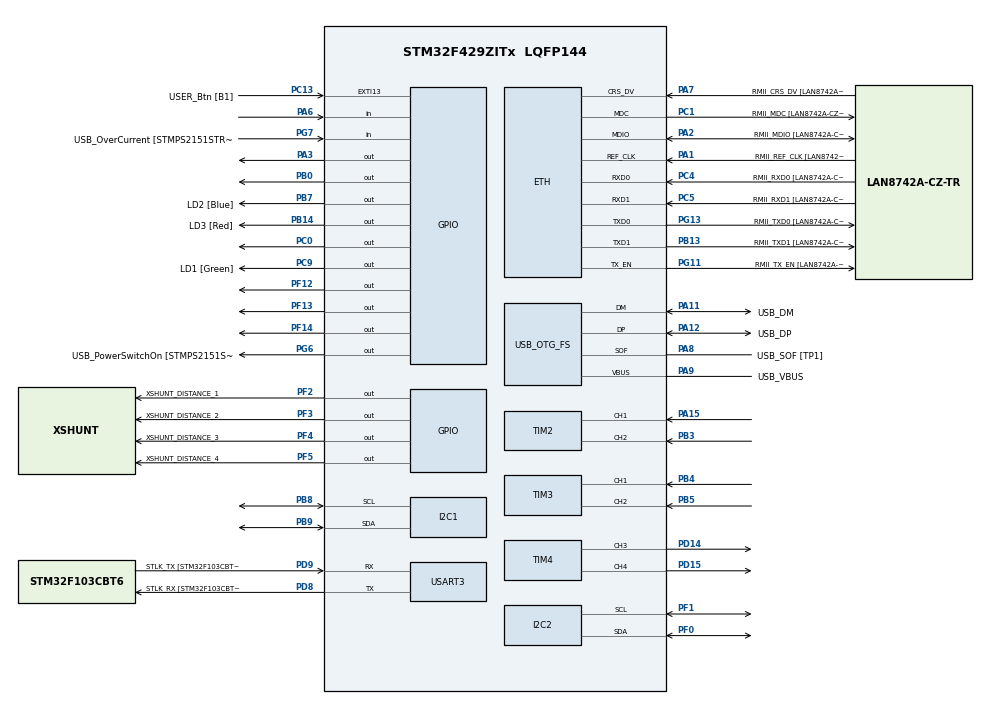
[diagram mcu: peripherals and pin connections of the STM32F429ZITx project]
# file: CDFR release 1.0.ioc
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ETH.MediaInterface=ETH_MEDIA_INTERFACE_RMII
ETH.PHY_Name=LAN8742A_PHY_ADDRESS
ETH.PHY_Value=0
ETH.PhyAddress=0
LWIP.CHECKSUM_BY_HARDWARE=1
LWIP.Version=v2.0.3_Cube
Mcu.Family=STM32F4
Mcu.Name=STM32F429ZITx
Mcu.Package=LQFP144
NVIC.OTG_FS_IRQn=true\:0\:0\:false\:false\:true\:false\:true
NVIC.PriorityGroup=NVIC_PRIORITYGROUP_4
NVIC.TIM8_UP_TIM13_IRQn=true\:5\:0\:true\:false\:true\:true\:true
PA1.GPIO_Label=RMII_REF_CLK [LAN8742A-CZ-TR_REFCLK0]
PA1.Mode=RMII
PA1.Signal=ETH_REF_CLK
PA10.GPIO_Label=USB_ID
PA10.Signal=USB_OTG_FS_ID
PA11.GPIO_Label=USB_DM
PA11.Mode=Device_Only
PA11.Signal=USB_OTG_FS_DM
PA12.GPIO_Label=USB_DP
PA12.Mode=Device_Only
PA12.Signal=USB_OTG_FS_DP
PA13.GPIO_Label=TMS
PA13.Mode=Serial_Wire
PA13.Signal=SYS_JTMS-SWDIO
PA14.GPIO_Label=TCK
PA14.Mode=Serial_Wire
PA14.Signal=SYS_JTCK-SWCLK
PA15.Signal=S_TIM2_CH1_ETR
PA2.GPIO_Label=RMII_MDIO [LAN8742A-CZ-TR_MDIO]
PA2.Mode=RMII
PA2.Signal=ETH_MDIO
PA3.Signal=GPIO_Output
PA6.Signal=GPIO_Input
PA7.GPIO_Label=RMII_CRS_DV [LAN8742A-CZ-TR_CRS_DV]
PA7.Mode=RMII
PA7.Signal=ETH_CRS_DV
PA8.GPIO_Label=USB_SOF [TP1]
PA8.Mode=Activate_SOF_FS
PA8.Signal=USB_OTG_FS_SOF
PA9.GPIO_Label=USB_VBUS
PA9.Mode=Activate_VBUS
PA9.Signal=USB_OTG_FS_VBUS
PB0.Signal=GPIO_Output
PB13.GPIO_Label=RMII_TXD1 [LAN8742A-CZ-TR_TXD1]
PB13.Mode=RMII
PB13.Signal=ETH_TXD1
PB14.GPIO_Label=LD3 [Red]
PB14.Signal=GPIO_Output
PB3.Signal=S_TIM2_CH2
PB4.Signal=S_TIM3_CH1
PB5.Signal=S_TIM3_CH2
PB7.GPIO_Label=LD2 [Blue]
PB7.Signal=GPIO_Output
PB8.Mode=I2C
PB8.Signal=I2C1_SCL
PB9.Mode=I2C
PB9.Signal=I2C1_SDA
PC0.Signal=GPIO_Output
PC1.GPIO_Label=RMII_MDC [LAN8742A-CZ-TR_MDC]
PC1.Mode=RMII
PC1.Signal=ETH_MDC
PC13.GPIO_Label=USER_Btn [B1]
PC13.Signal=GPXTI13
PC14/OSC32_IN.Mode=LSE-External-Oscillator
PC14/OSC32_IN.Signal=RCC_OSC32_IN
PC15/OSC32_OUT.Mode=LSE-External-Oscillator
PC15/OSC32_OUT.Signal=RCC_OSC32_OUT
PC4.GPIO_Label=RMII_RXD0 [LAN8742A-CZ-TR_RXD0]
PC4.Mode=RMII
PC4.Signal=ETH_RXD0
PC5.GPIO_Label=RMII_RXD1 [LAN8742A-CZ-TR_RXD1]
PC5.Mode=RMII
PC5.Signal=ETH_RXD1
PC9.GPIO_Label=LD1 [Green]
PC9.Signal=GPIO_Output
PD14.Signal=S_TIM4_CH3
PD15.Signal=S_TIM4_CH4
PD8.GPIO_Label=STLK_RX [STM32F103CBT6_PA3]
PD8.Mode=Asynchronous
PD8.Signal=USART3_TX
PD9.GPIO_Label=STLK_TX [STM32F103CBT6_PA2]
PD9.Mode=Asynchronous
PD9.Signal=USART3_RX
PF0.Mode=I2C
PF0.Signal=I2C2_SDA
PF1.Mode=I2C
PF1.Signal=I2C2_SCL
PF12.Signal=GPIO_Output
PF13.Signal=GPIO_Output
PF14.Signal=GPIO_Output
PF2.GPIO_Label=XSHUNT_DISTANCE_1
PF2.Signal=GPIO_Output
PF3.GPIO_Label=XSHUNT_DISTANCE_2
PF3.Signal=GPIO_Output
PF4.GPIO_Label=XSHUNT_DISTANCE_3
PF4.Signal=GPIO_Output
PF5.GPIO_Label=XSHUNT_DISTANCE_4
PF5.Signal=GPIO_Output
PG11.GPIO_Label=RMII_TX_EN [LAN8742A-CZ-TR_TXEN]
PG11.Mode=RMII
PG11.Signal=ETH_TX_EN
PG13.GPIO_Label=RMII_TXD0 [LAN8742A-CZ-TR_TXD0]
PG13.Mode=RMII
PG13.Signal=ETH_TXD0
PG6.GPIO_Label=USB_PowerSwitchOn [STMPS2151STR_EN]
PG6.Signal=GPIO_Output
PG7.GPIO_Label=USB_OverCurrent [STMPS2151STR_FAULT]
PG7.Signal=GPIO_Input
PH0/OSC_IN.GPIO_Label=MCO [STM32F103CBT6_PA8]
PH0/OSC_IN.Mode=HSE-External-Clock-Source
PH0/OSC_IN.Signal=RCC_OSC_IN
PH1/OSC_OUT.Mode=HSE-External-Clock-Source
PH1/OSC_OUT.Signal=RCC_OSC_OUT
ProjectManager.HeapSize=0x200
ProjectManager.StackSize=0x400
ProjectManager.TargetToolchain=STM32CubeIDE
RCC.48MHZClocksFreq_Value=48000000
RCC.AHBFreq_Value=168000000
RCC.APB1CLKDivider=RCC_HCLK_DIV4
RCC.APB1Freq_Value=42000000
RCC.APB1TimFreq_Value=84000000
RCC.APB2CLKDivider=RCC_HCLK_DIV2
RCC.APB2Freq_Value=84000000
RCC.APB2TimCLKDivider=2
RCC.APB2TimFreq_Value=168000000
RCC.CortexFreq_Value=168000000
RCC.HCLKFreq_Value=168000000
RCC.HSE_VALUE=8000000
RCC.HSI_VALUE=16000000
RCC.PLLM=4
RCC.PLLMUL=RCC_PLL_MUL9
RCC.PLLN=168
RCC.PLLQ=7
RCC.PRESCALERUSB=RCC_USBCLKSOURCE_PLL_DIV1_5
RCC.SYSCLKFreq_VALUE=168000000
RCC.SYSCLKSource=RCC_SYSCLKSOURCE_PLLCLK
RCC.SYSCLKSourceVirtual=RCC_SYSCLKSOURCE_PLLCLK
RCC.USBFreq_Value=48000000
RCC.VCOOutputFreq_Value=336000000
SH.S_TIM2_CH1_ETR.0=TIM2_CH1,Input_Capture1_from_TI1
SH.S_TIM2_CH2.0=TIM2_CH2,Input_Capture2_from_TI2
SH.S_TIM3_CH1.0=TIM3_CH1,Input_Capture1_from_TI1
SH.S_TIM3_CH2.0=TIM3_CH2,Input_Capture2_from_TI2
SH.S_TIM4_CH3.0=TIM4_CH3,PWM Generation3 CH3
SH.S_TIM4_CH4.0=TIM4_CH4,PWM Generation4 CH4
TIM13.AutoReloadPreload=TIM_AUTORELOAD_PRELOAD_ENABLE
TIM13.Period=1000
TIM13.Prescaler=8400
TIM2.Channel-Input_Capture1_from_TI1=TIM_CHANNEL_1
TIM2.Channel-Input_Capture2_from_TI2=TIM_CHANNEL_2
TIM3.Channel-Input_Capture1_from_TI1=TIM_CHANNEL_1
TIM3.Channel-Input_Capture2_from_TI2=TIM_CHANNEL_2
TIM4.Channel-PWM\ Generation3\ CH3=TIM_CHANNEL_3
TIM4.Channel-PWM\ Generation4\ CH4=TIM_CHANNEL_4
USART3.VirtualMode=VM_ASYNC
USB_DEVICE.CLASS_NAME_FS=CDC
USB_DEVICE.MANUFACTURER_STRING-CDC_FS=CDFR Carte ST
USB_DEVICE.VirtualMode-CDC_FS=Cdc
USB_DEVICE.VirtualModeFS=Cdc_FS
USB_OTG_FS.VirtualMode=Device_Only
VP_LWIP_VS_Enabled.Mode=Enabled
VP_TIM13_VS_ClockSourceINT.Mode=Enable_Timer
VP_USB_DEVICE_VS_USB_DEVICE_CDC_FS.Mode=CDC_FS
board=NUCLEO-F429ZI

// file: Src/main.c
/* USER CODE BEGIN Header */
/**
  ******************************************************************************
  * @file           : main.c
  * @brief          : Main program body
  ******************************************************************************
  * @attention
  *
  * <h2><center>&copy; Copyright (c) 2019 STMicroelectronics.
  * All rights reserved.</center></h2>
  *
  * This software component is licensed by ST under Ultimate Liberty license
  * SLA0044, the "License"; You may not use this file except in compliance with
  * the License. You may obtain a copy of the License at:
  *                             www.st.com/SLA0044
  *
  ******************************************************************************
  */
/* USER CODE END Header */

#include "main.h"
#include "i2c.h"
#include "lwip.h"
#include "tim.h"
#include "usart.h"
#include "usb_device.h"
#include "gpio.h"

/* USER CODE BEGIN Includes */
#include "tcp_server.h"
/* USER CODE END Includes */

/* USER CODE BEGIN PV */
extern Localisation g_estimate;
extern Localisation consigne[NB_POINT_MAX];
extern float g_errRightOld ;
extern float g_errLeftOld ;
extern int g_i_point;
extern int g_timer_9_cnt;
extern int g_temps_match;
extern int g_start_signal;
extern int g_stop_signal;

char g_uart_buff='^';
/* USER CODE END PV */

void SystemClock_Config(void);

int main(void)
{

  /* MCU Configuration--------------------------------------------------------*/

  /* Reset of all peripherals, Initializes the Flash interface and the Systick. */

	HAL_Init();

  /* Configure the system clock */
  SystemClock_Config();

  /* Initialize all configured peripherals */
  MX_GPIO_Init();
  MX_I2C1_Init();
  MX_I2C2_Init();
  MX_TIM2_Init();
  MX_TIM3_Init();
  MX_TIM4_Init();
  MX_USART3_UART_Init();
#if USE_TCP_SERVER == 1
  MX_LWIP_Init();
#endif
  MX_USB_DEVICE_Init();
  MX_TIM13_Init();

  /* USER CODE BEGIN 2 */
#if PRINTF_USB_UART == 1
  printf("Initializing the VL53L1X sensors....\r\n");
#endif
  F_VL53L1X_InitSensors();

  TIM13->DIER |= TIM_DIER_UIE;	// Enable interrupt
  TIM13->CR1 |= TIM_CR1_CEN;

  Init_Motors();
  Init_QEI();
  Init_Timer9();
  Init_Timer10();

    // Initialize the TCP Echo Server
#if PRINTF_USB_UART == 1
  printf("Initializing the TCP server....\r\n");
#endif
  F_GPIO_SetLedRed(1);
#if USE_TCP_SERVER == 1
      tcp_server_init();
#endif

 /* F_QEI_setPosition(100,-727,0);

  F_AUTO_AddTargetPoint(200 , -727, 0);
  F_AUTO_AddTargetPoint(200 , -1350, 0);
  F_AUTO_AddTargetPoint(900 , -1350, 0);
  F_AUTO_AddTargetPoint(300 , -727, 180);

*/

  int dcG=0,dcD=0,bp_flag=0,dutyC=25;
  float speedL,speedR;
  int angleDeg=90;

 // while(F_GPIO_GetTirette() == 1);

 // F_AUTO_Enable();

  F_Init_TimerServo();
  F_Servo_Fermer();

#if PRINTF_USB_UART == 1
  printf("Entering the infinite loop....\r\n");
#endif
  /* USER CODE END 2 */

  /* Infinite loop */
  while (1)
  {

	     /* USER CODE BEGIN 3 */

	  // Handle the TCP connection
#if USE_TCP_SERVER == 1
	  MX_LWIP_Process();
#endif
  }
  /* USER CODE END 3 */
}

void SystemClock_Config(void)
{
  RCC_OscInitTypeDef RCC_OscInitStruct = {0};
  RCC_ClkInitTypeDef RCC_ClkInitStruct = {0};

  /** Configure the main internal regulator output voltage
  */
  __HAL_RCC_PWR_CLK_ENABLE();
  __HAL_PWR_VOLTAGESCALING_CONFIG(PWR_REGULATOR_VOLTAGE_SCALE1);
  /** Initializes the CPU, AHB and APB busses clocks
  */
  RCC_OscInitStruct.OscillatorType = RCC_OSCILLATORTYPE_HSE;
  RCC_OscInitStruct.HSEState = RCC_HSE_BYPASS;
  RCC_OscInitStruct.PLL.PLLState = RCC_PLL_ON;
  RCC_OscInitStruct.PLL.PLLSource = RCC_PLLSOURCE_HSE;
  RCC_OscInitStruct.PLL.PLLM = 4;
  RCC_OscInitStruct.PLL.PLLN = 180;
  RCC_OscInitStruct.PLL.PLLP = RCC_PLLP_DIV2;
  RCC_OscInitStruct.PLL.PLLQ = 7;
  if (HAL_RCC_OscConfig(&RCC_OscInitStruct) != HAL_OK)
  {
    Error_Handler();
  }
  /** Initializes the CPU, AHB and APB busses clocks
  */
  RCC_ClkInitStruct.ClockType = RCC_CLOCKTYPE_HCLK|RCC_CLOCKTYPE_SYSCLK
                              |RCC_CLOCKTYPE_PCLK1|RCC_CLOCKTYPE_PCLK2;
  RCC_ClkInitStruct.SYSCLKSource = RCC_SYSCLKSOURCE_PLLCLK;
  RCC_ClkInitStruct.AHBCLKDivider = RCC_SYSCLK_DIV1;
  RCC_ClkInitStruct.APB1CLKDivider = RCC_HCLK_DIV4;
  RCC_ClkInitStruct.APB2CLKDivider = RCC_HCLK_DIV2;

  if (HAL_RCC_ClockConfig(&RCC_ClkInitStruct, FLASH_LATENCY_5) != HAL_OK)
  {
    Error_Handler();
  }
}

void Error_Handler(void)
{
}

/************************ (C) COPYRIGHT STMicroelectronics *****END OF FILE****/
